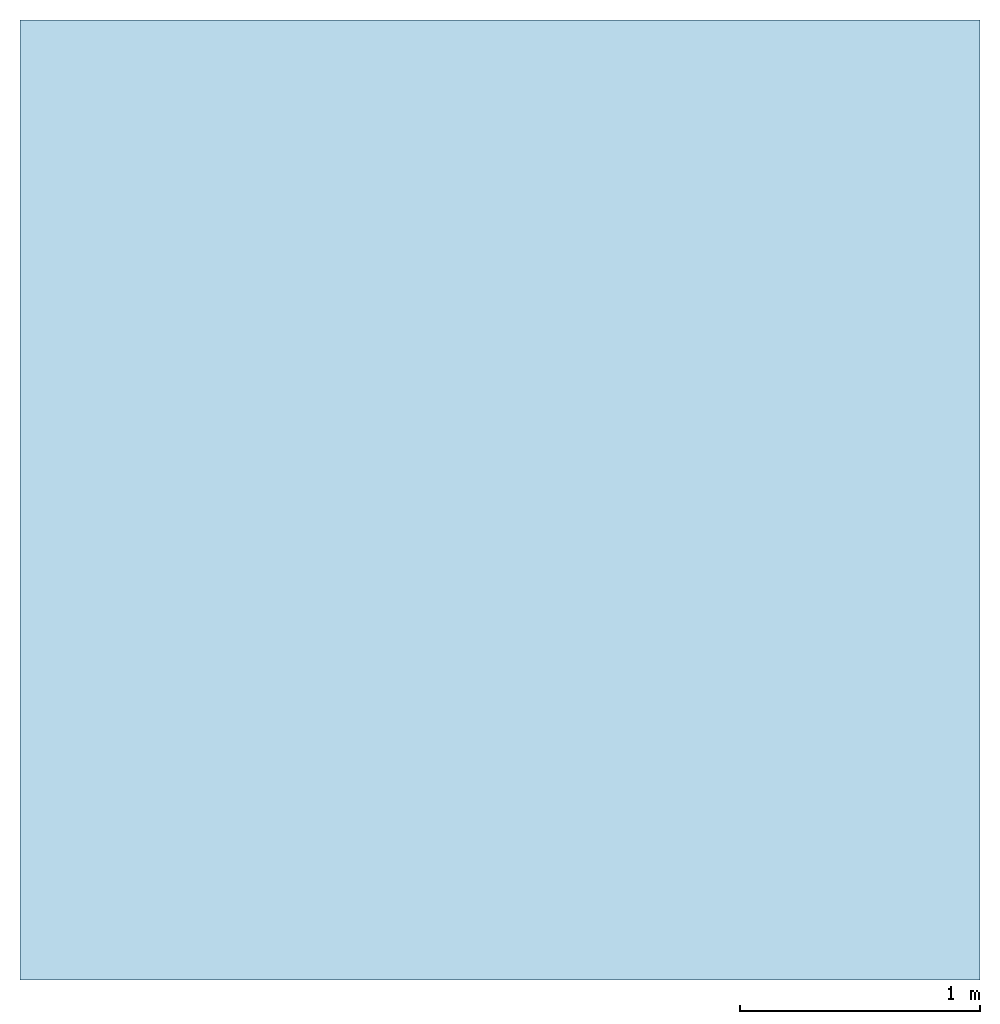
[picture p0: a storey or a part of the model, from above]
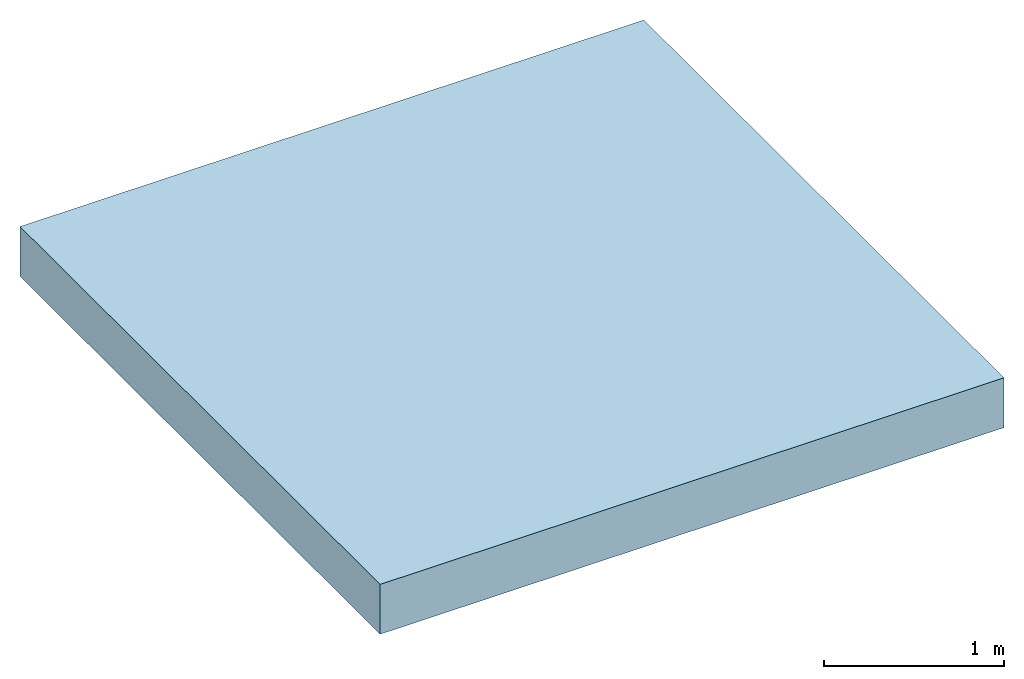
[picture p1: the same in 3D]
Properties of the parts of a building model (IFC2X3)

# File
Description: ViewDefinition [CoordinationView_V2.0]
File name: 0001
Time: 2021-07-30T08:46:24
Written by: The EXPRESS Data Manager Version 5.02.0100.07 : 28 Aug 2013
Made in: 20190108_1515(x64) - Exporter 19.2.1.1 - IU alternativa 19.2.1.1
Comment: STEP Physical File produced by: The EXPRESS Data Manager Version 5.02.0100.07 : 28 Aug 2013 * Module: EDMstepFileFactory/EDMstandAlone * Creation date: Fri Jul 30 08:46:24 2021 * Host: DESKTOP-9PSOHM7 * Database: C:\Users\MODELA~1\AppData\Local\Temp\{D233DA67-3B2A-4BA0-9E0E-E226E47BA596}\ifc * Database version: 5507 * Database creation date: Fri Jul 30 08:46:24 2021 * Schema: IFC2X3 * Model: DataRepository.ifc * Model creation date: Fri Jul 30 08:46:24 2021 * Header model: DataRepository.ifc_HeaderModel * Header model creation date: Fri Jul 30 08:46:24 2021 * EDMuser: sdai-user * EDMgroup: sdai-group * License ID and type: 5605 : Permanent license. Expiry date: * EDMstepFileFactory options: 020000

# IfcProject, 0001
LongName: Nombre de proyecto; Phase: Estado de proyecto

# IfcSite, Default
RefLatitude: 40, 24, 0, 5493; RefLongitude: -3, -40, -59, -880065; RefElevation: 0 mm

# IfcBuilding
Pset_BuildingCommon - NumberOfStoreys: 1

# IfcBuildingStorey, Nivel 1
LongName: Nivel 1; Elevation: 0 mm

# IfcRoof: Cubierta básica:CubiertaPlanaConvenTrans-PeatonesPúblico_SoladoFijoBaldosaCeramica_BCTIB7SA, Cubierta básica:CubiertaPlanaConvenTrans-PeatonesPúblico_SoladoFijoBaldosaCeramica_BCTIB7SA:132469
In: Nivel 1
Pset_RoofCommon - Reference: CubiertaPlanaConvenTrans-PeatonesPúblico_SoladoFijoBaldosaCeramica_BCTIB7SA; IsExternal: yes; TotalArea: 16 m2; ProjectedArea: 16 m2
Pset_ManufacturerTypeInformation - Manufacturer: Chova

# IfcSlab: Cubierta básica:CubiertaPlanaConvenTrans-PeatonesPúblico_SoladoFijoBaldosaCeramica_BCTIB7SA, Cubierta básica:CubiertaPlanaConvenTrans-PeatonesPúblico_SoladoFijoBaldosaCeramica_BCTIB7SA:132469
In: Nivel 1
PredefinedType: ROOF; Material: Baldosas con mortero de agarre 30 mm, IM_Poliester_Geotextil_Geofim200 2 mm, IM_LaminaAsfaltica_Lamina_PolitaberCombi40 (LBM 40-FP) 2 mm, IM_LaminaAsfaltica_Lamina_PolitaberVel30 (LBM 30-FV) 2 mm, IM_EmulsionBituminosa_Bote_Supermul 2 mm, Formación de pendientes 50 mm, Soporte resistente 250 mm
Pset_SlabCommon - Reference: CubiertaPlanaConvenTrans-PeatonesPúblico_SoladoFijoBaldosaCeramica_BCTIB7SA; IsExternal: yes; ThermalTransmittance: 11.1772 kg/K/s3; PitchAngle: 0 deg
Pset_ManufacturerTypeInformation - Manufacturer: Chova
